VERSION 5.7 ;
  NOWIREEXTENSIONATPIN ON ;
  DIVIDERCHAR "/" ;
  BUSBITCHARS "[]" ;
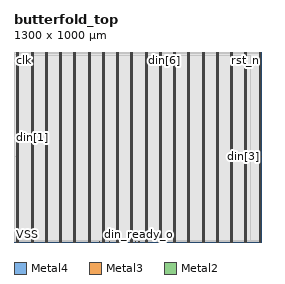
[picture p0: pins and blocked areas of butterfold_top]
MACRO butterfold_top
  CLASS BLOCK ;
  FOREIGN butterfold_top ;
  ORIGIN 0.000 0.000 ;
  SIZE 1300.000 BY 1000.000 ;
  PIN VDD
    DIRECTION INOUT ;
    USE POWER ;
    PORT
      LAYER Metal4 ;
        RECT 14.940 0.000 19.940 1000.000 ;
    END
    PORT
      LAYER Metal4 ;
        RECT 89.940 0.000 94.940 1000.000 ;
    END
    PORT
      LAYER Metal4 ;
        RECT 164.940 0.000 169.940 1000.000 ;
    END
    PORT
      LAYER Metal4 ;
        RECT 239.940 0.000 244.940 1000.000 ;
    END
    PORT
      LAYER Metal4 ;
        RECT 314.940 0.000 319.940 1000.000 ;
    END
    PORT
      LAYER Metal4 ;
        RECT 389.940 0.000 394.940 1000.000 ;
    END
    PORT
      LAYER Metal4 ;
        RECT 464.940 0.000 469.940 1000.000 ;
    END
    PORT
      LAYER Metal4 ;
        RECT 539.940 0.000 544.940 1000.000 ;
    END
    PORT
      LAYER Metal4 ;
        RECT 614.940 0.000 619.940 1000.000 ;
    END
    PORT
      LAYER Metal4 ;
        RECT 689.940 0.000 694.940 1000.000 ;
    END
    PORT
      LAYER Metal4 ;
        RECT 764.940 0.000 769.940 1000.000 ;
    END
    PORT
      LAYER Metal4 ;
        RECT 839.940 0.000 844.940 1000.000 ;
    END
    PORT
      LAYER Metal4 ;
        RECT 914.940 0.000 919.940 1000.000 ;
    END
    PORT
      LAYER Metal4 ;
        RECT 989.940 0.000 994.940 1000.000 ;
    END
    PORT
      LAYER Metal4 ;
        RECT 1064.940 0.000 1069.940 1000.000 ;
    END
    PORT
      LAYER Metal4 ;
        RECT 1139.940 0.000 1144.940 1000.000 ;
    END
    PORT
      LAYER Metal4 ;
        RECT 1214.940 0.000 1219.940 1000.000 ;
    END
    PORT
      LAYER Metal4 ;
        RECT 1289.940 0.000 1294.940 1000.000 ;
    END
  END VDD
  PIN VSS
    DIRECTION INOUT ;
    USE GROUND ;
    PORT
      LAYER Metal4 ;
        RECT 20.940 0.000 25.940 1000.000 ;
    END
    PORT
      LAYER Metal4 ;
        RECT 95.940 0.000 100.940 1000.000 ;
    END
    PORT
      LAYER Metal4 ;
        RECT 170.940 0.000 175.940 1000.000 ;
    END
    PORT
      LAYER Metal4 ;
        RECT 245.940 0.000 250.940 1000.000 ;
    END
    PORT
      LAYER Metal4 ;
        RECT 320.940 0.000 325.940 1000.000 ;
    END
    PORT
      LAYER Metal4 ;
        RECT 395.940 0.000 400.940 1000.000 ;
    END
    PORT
      LAYER Metal4 ;
        RECT 470.940 0.000 475.940 1000.000 ;
    END
    PORT
      LAYER Metal4 ;
        RECT 545.940 0.000 550.940 1000.000 ;
    END
    PORT
      LAYER Metal4 ;
        RECT 620.940 0.000 625.940 1000.000 ;
    END
    PORT
      LAYER Metal4 ;
        RECT 695.940 0.000 700.940 1000.000 ;
    END
    PORT
      LAYER Metal4 ;
        RECT 770.940 0.000 775.940 1000.000 ;
    END
    PORT
      LAYER Metal4 ;
        RECT 845.940 0.000 850.940 1000.000 ;
    END
    PORT
      LAYER Metal4 ;
        RECT 920.940 0.000 925.940 1000.000 ;
    END
    PORT
      LAYER Metal4 ;
        RECT 995.940 0.000 1000.940 1000.000 ;
    END
    PORT
      LAYER Metal4 ;
        RECT 1070.940 0.000 1075.940 1000.000 ;
    END
    PORT
      LAYER Metal4 ;
        RECT 1145.940 0.000 1150.940 1000.000 ;
    END
    PORT
      LAYER Metal4 ;
        RECT 1220.940 0.000 1225.940 1000.000 ;
    END
  END VSS
  PIN clk
    DIRECTION INPUT ;
    USE SIGNAL ;
    ANTENNAGATEAREA 9.476000 ;
    ANTENNADIFFAREA 0.820800 ;
    PORT
      LAYER Metal3 ;
        RECT 0.000 987.840 0.560 988.400 ;
    END
  END clk
  PIN din[0]
    DIRECTION INPUT ;
    USE SIGNAL ;
    ANTENNAGATEAREA 0.498500 ;
    ANTENNADIFFAREA 0.410400 ;
    PORT
      LAYER Metal2 ;
        RECT 502.880 0.000 503.440 0.560 ;
    END
  END din[0]
  PIN din[1]
    DIRECTION INPUT ;
    USE SIGNAL ;
    ANTENNAGATEAREA 0.396000 ;
    ANTENNADIFFAREA 0.410400 ;
    PORT
      LAYER Metal3 ;
        RECT 0.000 548.800 0.560 549.360 ;
    END
  END din[1]
  PIN din[2]
    DIRECTION INPUT ;
    USE SIGNAL ;
    ANTENNAGATEAREA 0.396000 ;
    ANTENNADIFFAREA 0.410400 ;
    PORT
      LAYER Metal2 ;
        RECT 449.120 0.000 449.680 0.560 ;
    END
  END din[2]
  PIN din[3]
    DIRECTION INPUT ;
    USE SIGNAL ;
    ANTENNAGATEAREA 0.498500 ;
    ANTENNADIFFAREA 0.410400 ;
    PORT
      LAYER Metal3 ;
        RECT 1299.440 449.120 1300.000 449.680 ;
    END
  END din[3]
  PIN din[4]
    DIRECTION INPUT ;
    USE SIGNAL ;
    ANTENNAGATEAREA 0.396000 ;
    ANTENNADIFFAREA 0.410400 ;
    PORT
      LAYER Metal2 ;
        RECT 450.240 0.000 450.800 0.560 ;
    END
  END din[4]
  PIN din[5]
    DIRECTION INPUT ;
    USE SIGNAL ;
    ANTENNAGATEAREA 0.396000 ;
    ANTENNADIFFAREA 0.410400 ;
    PORT
      LAYER Metal2 ;
        RECT 451.360 0.000 451.920 0.560 ;
    END
  END din[5]
  PIN din[6]
    DIRECTION INPUT ;
    USE SIGNAL ;
    ANTENNAGATEAREA 0.498500 ;
    ANTENNADIFFAREA 0.410400 ;
    PORT
      LAYER Metal2 ;
        RECT 791.840 999.440 792.400 1000.000 ;
    END
  END din[6]
  PIN din[7]
    DIRECTION INPUT ;
    USE SIGNAL ;
    ANTENNAGATEAREA 0.498500 ;
    ANTENNADIFFAREA 0.410400 ;
    PORT
      LAYER Metal3 ;
        RECT 1299.440 450.240 1300.000 450.800 ;
    END
  END din[7]
  PIN din_ready_o
    DIRECTION OUTPUT ;
    USE SIGNAL ;
    ANTENNADIFFAREA 1.008600 ;
    PORT
      LAYER Metal2 ;
        RECT 657.440 0.000 658.000 0.560 ;
    END
  END din_ready_o
  PIN din_valid_i
    DIRECTION INPUT ;
    USE SIGNAL ;
    ANTENNAGATEAREA 0.498500 ;
    ANTENNADIFFAREA 0.410400 ;
    PORT
      LAYER Metal2 ;
        RECT 640.640 0.000 641.200 0.560 ;
    END
  END din_valid_i
  PIN dout[0]
    DIRECTION OUTPUT ;
    USE SIGNAL ;
    ANTENNADIFFAREA 0.897600 ;
    PORT
      LAYER Metal2 ;
        RECT 700.000 999.440 700.560 1000.000 ;
    END
  END dout[0]
  PIN dout[1]
    DIRECTION OUTPUT ;
    USE SIGNAL ;
    ANTENNADIFFAREA 1.008600 ;
    PORT
      LAYER Metal2 ;
        RECT 733.600 999.440 734.160 1000.000 ;
    END
  END dout[1]
  PIN dout[2]
    DIRECTION OUTPUT ;
    USE SIGNAL ;
    ANTENNADIFFAREA 0.897600 ;
    PORT
      LAYER Metal2 ;
        RECT 702.240 999.440 702.800 1000.000 ;
    END
  END dout[2]
  PIN dout[3]
    DIRECTION OUTPUT ;
    USE SIGNAL ;
    ANTENNADIFFAREA 0.897600 ;
    PORT
      LAYER Metal2 ;
        RECT 760.480 999.440 761.040 1000.000 ;
    END
  END dout[3]
  PIN dout[4]
    DIRECTION OUTPUT ;
    USE SIGNAL ;
    ANTENNADIFFAREA 0.897600 ;
    PORT
      LAYER Metal2 ;
        RECT 707.840 999.440 708.400 1000.000 ;
    END
  END dout[4]
  PIN dout[5]
    DIRECTION OUTPUT ;
    USE SIGNAL ;
    ANTENNADIFFAREA 0.897600 ;
    PORT
      LAYER Metal2 ;
        RECT 757.120 999.440 757.680 1000.000 ;
    END
  END dout[5]
  PIN dout[6]
    DIRECTION OUTPUT ;
    USE SIGNAL ;
    ANTENNADIFFAREA 0.897600 ;
    PORT
      LAYER Metal2 ;
        RECT 698.880 999.440 699.440 1000.000 ;
    END
  END dout[6]
  PIN dout[7]
    DIRECTION OUTPUT ;
    USE SIGNAL ;
    ANTENNADIFFAREA 0.897600 ;
    PORT
      LAYER Metal2 ;
        RECT 685.440 999.440 686.000 1000.000 ;
    END
  END dout[7]
  PIN dout_valid_o
    DIRECTION OUTPUT ;
    USE SIGNAL ;
    ANTENNADIFFAREA 0.897600 ;
    PORT
      LAYER Metal2 ;
        RECT 621.600 0.000 622.160 0.560 ;
    END
  END dout_valid_o
  PIN rst_n
    DIRECTION INPUT ;
    USE SIGNAL ;
    ANTENNAGATEAREA 0.396000 ;
    ANTENNADIFFAREA 0.410400 ;
    PORT
      LAYER Metal2 ;
        RECT 1221.920 999.440 1222.480 1000.000 ;
    END
  END rst_n
  OBS
      LAYER Nwell ;
        RECT 0.690 3.490 1299.070 996.110 ;
      LAYER Metal1 ;
        RECT 1.120 3.620 1298.640 995.980 ;
      LAYER Metal2 ;
        RECT 2.380 999.140 685.140 999.860 ;
        RECT 686.300 999.140 698.580 999.860 ;
        RECT 700.860 999.140 701.940 999.860 ;
        RECT 703.100 999.140 707.540 999.860 ;
        RECT 708.700 999.140 733.300 999.860 ;
        RECT 734.460 999.140 756.820 999.860 ;
        RECT 757.980 999.140 760.180 999.860 ;
        RECT 761.340 999.140 791.540 999.860 ;
        RECT 792.700 999.140 1221.620 999.860 ;
        RECT 1222.780 999.140 1297.380 999.860 ;
        RECT 2.380 0.860 1297.380 999.140 ;
        RECT 2.380 0.560 448.820 0.860 ;
        RECT 452.220 0.560 502.580 0.860 ;
        RECT 503.740 0.560 621.300 0.860 ;
        RECT 622.460 0.560 640.340 0.860 ;
        RECT 641.500 0.560 657.140 0.860 ;
        RECT 658.300 0.560 1297.380 0.860 ;
      LAYER Metal3 ;
        RECT 0.560 988.700 1299.440 996.100 ;
        RECT 0.860 987.540 1299.440 988.700 ;
        RECT 0.560 549.660 1299.440 987.540 ;
        RECT 0.860 548.500 1299.440 549.660 ;
        RECT 0.560 451.100 1299.440 548.500 ;
        RECT 0.560 448.820 1299.140 451.100 ;
        RECT 0.560 2.940 1299.440 448.820 ;
      LAYER Metal4 ;
        RECT 14.140 5.690 14.640 993.350 ;
        RECT 20.240 5.690 20.640 993.350 ;
        RECT 26.240 5.690 89.640 993.350 ;
        RECT 95.240 5.690 95.640 993.350 ;
        RECT 101.240 5.690 164.640 993.350 ;
        RECT 170.240 5.690 170.640 993.350 ;
        RECT 176.240 5.690 239.640 993.350 ;
        RECT 245.240 5.690 245.640 993.350 ;
        RECT 251.240 5.690 314.640 993.350 ;
        RECT 320.240 5.690 320.640 993.350 ;
        RECT 326.240 5.690 389.640 993.350 ;
        RECT 395.240 5.690 395.640 993.350 ;
        RECT 401.240 5.690 464.640 993.350 ;
        RECT 470.240 5.690 470.640 993.350 ;
        RECT 476.240 5.690 539.640 993.350 ;
        RECT 545.240 5.690 545.640 993.350 ;
        RECT 551.240 5.690 614.640 993.350 ;
        RECT 620.240 5.690 620.640 993.350 ;
        RECT 626.240 5.690 689.640 993.350 ;
        RECT 695.240 5.690 695.640 993.350 ;
        RECT 701.240 5.690 764.640 993.350 ;
        RECT 770.240 5.690 770.640 993.350 ;
        RECT 776.240 5.690 839.640 993.350 ;
        RECT 845.240 5.690 845.640 993.350 ;
        RECT 851.240 5.690 914.640 993.350 ;
        RECT 920.240 5.690 920.640 993.350 ;
        RECT 926.240 5.690 989.640 993.350 ;
        RECT 995.240 5.690 995.640 993.350 ;
        RECT 1001.240 5.690 1064.640 993.350 ;
        RECT 1070.240 5.690 1070.640 993.350 ;
        RECT 1076.240 5.690 1139.640 993.350 ;
        RECT 1145.240 5.690 1145.640 993.350 ;
        RECT 1151.240 5.690 1214.640 993.350 ;
        RECT 1220.240 5.690 1220.640 993.350 ;
        RECT 1226.240 5.690 1289.540 993.350 ;
      LAYER Metal5 ;
        RECT 101.420 6.530 1243.140 982.570 ;
  END
END butterfold_top
END LIBRARY

